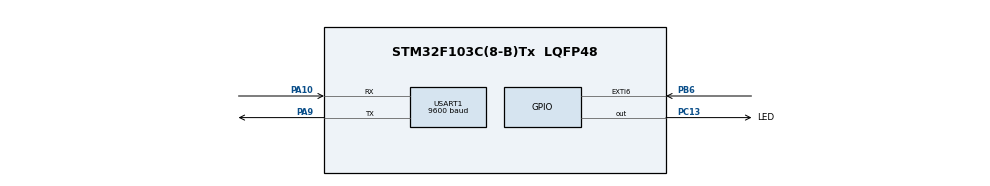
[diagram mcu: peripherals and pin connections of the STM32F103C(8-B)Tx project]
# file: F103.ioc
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Mcu.Family=STM32F1
Mcu.Name=STM32F103C(8-B)Tx
Mcu.Package=LQFP48
NVIC.FLASH_IRQn=true\:0\:0\:false\:false\:true\:true\:false
NVIC.PVD_IRQn=true\:0\:0\:false\:false\:true\:true\:false
NVIC.PriorityGroup=NVIC_PRIORITYGROUP_0
NVIC.RCC_IRQn=true\:0\:11\:false\:false\:true\:true\:false
NVIC.USART1_IRQn=true\:0\:15\:true\:false\:true\:true\:false
PA10.Mode=Asynchronous
PA10.Signal=USART1_RX
PA13.GPIO_Label=SYS
PA13.Mode=Serial_Wire
PA13.Signal=SYS_JTMS-SWDIO
PA14.GPIO_Label=SYS
PA14.Mode=Serial_Wire
PA14.Signal=SYS_JTCK-SWCLK
PA9.Mode=Asynchronous
PA9.Signal=USART1_TX
PB6.Signal=GPXTI6
PC13-TAMPER-RTC.GPIO_Label=LED
PC13-TAMPER-RTC.GPIO_ModeDefaultOutputPP=GPIO_MODE_OUTPUT_PP
PC13-TAMPER-RTC.GPIO_PuPd=GPIO_PULLUP
PC13-TAMPER-RTC.GPIO_Speed=GPIO_SPEED_FREQ_MEDIUM
PC13-TAMPER-RTC.Signal=GPIO_Output
PC14-OSC32_IN.Mode=LSE-External-Clock-Source
PC14-OSC32_IN.Signal=RCC_OSC32_IN
PC15-OSC32_OUT.Mode=LSE-External-Clock-Source
PC15-OSC32_OUT.Signal=RCC_OSC32_OUT
PD0-OSC_IN.Mode=HSE-External-Clock-Source
PD0-OSC_IN.Signal=RCC_OSC_IN
PD1-OSC_OUT.Mode=HSE-External-Clock-Source
PD1-OSC_OUT.Signal=RCC_OSC_OUT
ProjectManager.HeapSize=0x200
ProjectManager.StackSize=0x400
ProjectManager.TargetToolchain=MDK-ARM V5.27
RCC.AHBFreq_Value=72000000
RCC.APB1CLKDivider=RCC_HCLK_DIV2
RCC.APB1Freq_Value=36000000
RCC.APB1TimFreq_Value=72000000
RCC.APB2Freq_Value=72000000
RCC.APB2TimFreq_Value=72000000
RCC.HCLKFreq_Value=72000000
RCC.PLLMUL=RCC_PLL_MUL9
RCC.PLLSourceVirtual=RCC_PLLSOURCE_HSE
RCC.SYSCLKFreq_VALUE=72000000
RCC.SYSCLKSource=RCC_SYSCLKSOURCE_PLLCLK
RCC.USBFreq_Value=72000000
USART1.BaudRate=9600
USART1.VirtualMode=VM_ASYNC
board=custom

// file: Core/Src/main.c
/* USER CODE BEGIN Header */
/**
  ******************************************************************************
  * @file           : main.c
  * @brief          : Main program body
  ******************************************************************************
  * @attention
  *
  * <h2><center>&copy; Copyright (c) 2020 STMicroelectronics.
  * All rights reserved.</center></h2>
  *
  * This software component is licensed by ST under BSD 3-Clause license,
  * the "License"; You may not use this file except in compliance with the
  * License. You may obtain a copy of the License at:
  *                        opensource.org/licenses/BSD-3-Clause
  *
  ******************************************************************************
  */
/* USER CODE END Header */
#include "main.h"

UART_HandleTypeDef huart1;

void SystemClock_Config(void);
static void MX_GPIO_Init(void);
static void MX_USART1_UART_Init(void);

int main(void)
{

  /* MCU Configuration--------------------------------------------------------*/

  /* Reset of all peripherals, Initializes the Flash interface and the Systick. */
  HAL_Init();

  /* Configure the system clock */
  SystemClock_Config();

  /* Initialize all configured peripherals */
  MX_GPIO_Init();
  MX_USART1_UART_Init();

  /* Infinite loop */
  while (1)
  {

  }
}

void SystemClock_Config(void)
{
  RCC_OscInitTypeDef RCC_OscInitStruct = {0};
  RCC_ClkInitTypeDef RCC_ClkInitStruct = {0};

  /** Initializes the RCC Oscillators according to the specified parameters
  * in the RCC_OscInitTypeDef structure.
  */
  RCC_OscInitStruct.OscillatorType = RCC_OSCILLATORTYPE_HSI;
  RCC_OscInitStruct.HSIState = RCC_HSI_ON;
  RCC_OscInitStruct.HSICalibrationValue = RCC_HSICALIBRATION_DEFAULT;
  RCC_OscInitStruct.PLL.PLLState = RCC_PLL_ON;
  RCC_OscInitStruct.PLL.PLLSource = RCC_PLLSOURCE_HSI_DIV2;
  RCC_OscInitStruct.PLL.PLLMUL = RCC_PLL_MUL16;
  if (HAL_RCC_OscConfig(&RCC_OscInitStruct) != HAL_OK)
  {
    Error_Handler();
  }
  /** Initializes the CPU, AHB and APB buses clocks
  */
  RCC_ClkInitStruct.ClockType = RCC_CLOCKTYPE_HCLK|RCC_CLOCKTYPE_SYSCLK
                              |RCC_CLOCKTYPE_PCLK1|RCC_CLOCKTYPE_PCLK2;
  RCC_ClkInitStruct.SYSCLKSource = RCC_SYSCLKSOURCE_PLLCLK;
  RCC_ClkInitStruct.AHBCLKDivider = RCC_SYSCLK_DIV1;
  RCC_ClkInitStruct.APB1CLKDivider = RCC_HCLK_DIV8;
  RCC_ClkInitStruct.APB2CLKDivider = RCC_HCLK_DIV1;

  if (HAL_RCC_ClockConfig(&RCC_ClkInitStruct, FLASH_LATENCY_2) != HAL_OK)
  {
    Error_Handler();
  }
}

static void MX_USART1_UART_Init(void)
{

  huart1.Instance = USART1;
  huart1.Init.BaudRate = 9600;
  huart1.Init.WordLength = UART_WORDLENGTH_8B;
  huart1.Init.StopBits = UART_STOPBITS_1;
  huart1.Init.Parity = UART_PARITY_NONE;
  huart1.Init.Mode = UART_MODE_TX_RX;
  huart1.Init.HwFlowCtl = UART_HWCONTROL_NONE;
  huart1.Init.OverSampling = UART_OVERSAMPLING_16;
  if (HAL_UART_Init(&huart1) != HAL_OK)
  {
    Error_Handler();
  }

}

static void MX_GPIO_Init(void)
{
  GPIO_InitTypeDef GPIO_InitStruct = {0};

  /* GPIO Ports Clock Enable */
  __HAL_RCC_GPIOC_CLK_ENABLE();
  __HAL_RCC_GPIOA_CLK_ENABLE();
  __HAL_RCC_GPIOB_CLK_ENABLE();

  /*Configure GPIO pin Output Level */
  HAL_GPIO_WritePin(LED_GPIO_Port, LED_Pin, GPIO_PIN_RESET);

  /*Configure GPIO pin : LED_Pin */
  GPIO_InitStruct.Pin = LED_Pin;
  GPIO_InitStruct.Mode = GPIO_MODE_OUTPUT_PP;
  GPIO_InitStruct.Pull = GPIO_PULLUP;
  GPIO_InitStruct.Speed = GPIO_SPEED_FREQ_MEDIUM;
  HAL_GPIO_Init(LED_GPIO_Port, &GPIO_InitStruct);

  /*Configure GPIO pin : PB6 */
  GPIO_InitStruct.Pin = GPIO_PIN_6;
  GPIO_InitStruct.Mode = GPIO_MODE_IT_RISING;
  GPIO_InitStruct.Pull = GPIO_NOPULL;
  HAL_GPIO_Init(GPIOB, &GPIO_InitStruct);

}

void Error_Handler(void)
{
}

/************************ (C) COPYRIGHT STMicroelectronics *****END OF FILE****/
